VERSION 5.7 ;
BUSBITCHARS "[]" ;
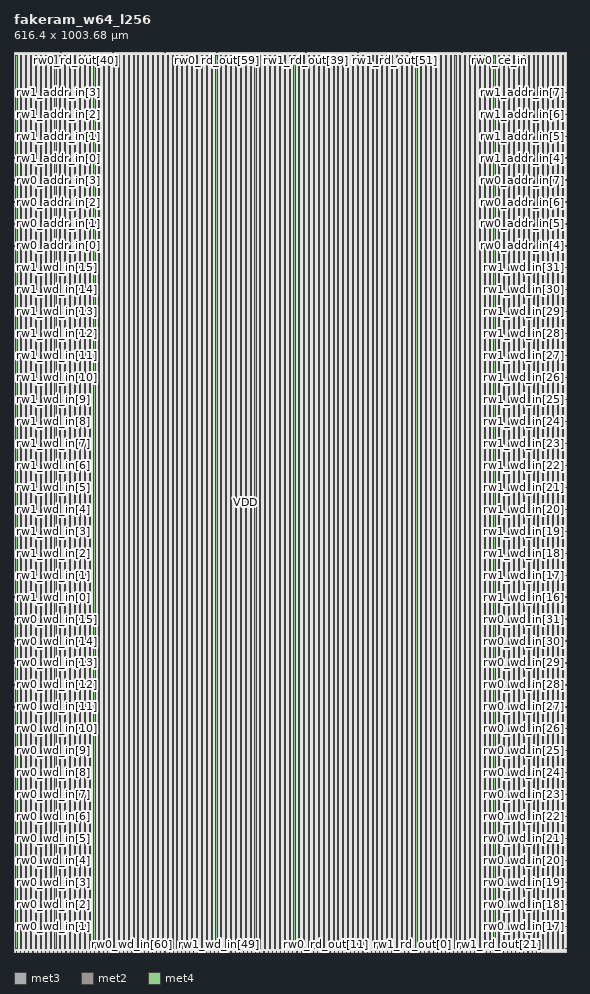
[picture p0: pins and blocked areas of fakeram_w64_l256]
MACRO fakeram_w64_l256
  FOREIGN fakeram_w64_l256 0 0 ;
  SYMMETRY X Y R90 ;
  SIZE 616.400 BY 1003.680 ;
  CLASS BLOCK ;
  PIN rw0_wd_in[0]
    DIRECTION INPUT ;
    USE SIGNAL ;
    SHAPE ABUTMENT ;
    PORT
      LAYER met3 ;
      RECT 0.000 3.930 0.900 4.230 ;
    END
  END rw0_wd_in[0]
  PIN rw0_wd_in[1]
    DIRECTION INPUT ;
    USE SIGNAL ;
    SHAPE ABUTMENT ;
    PORT
      LAYER met3 ;
      RECT 0.000 28.410 0.900 28.710 ;
    END
  END rw0_wd_in[1]
  PIN rw0_wd_in[2]
    DIRECTION INPUT ;
    USE SIGNAL ;
    SHAPE ABUTMENT ;
    PORT
      LAYER met3 ;
      RECT 0.000 52.890 0.900 53.190 ;
    END
  END rw0_wd_in[2]
  PIN rw0_wd_in[3]
    DIRECTION INPUT ;
    USE SIGNAL ;
    SHAPE ABUTMENT ;
    PORT
      LAYER met3 ;
      RECT 0.000 77.370 0.900 77.670 ;
    END
  END rw0_wd_in[3]
  PIN rw0_wd_in[4]
    DIRECTION INPUT ;
    USE SIGNAL ;
    SHAPE ABUTMENT ;
    PORT
      LAYER met3 ;
      RECT 0.000 101.850 0.900 102.150 ;
    END
  END rw0_wd_in[4]
  PIN rw0_wd_in[5]
    DIRECTION INPUT ;
    USE SIGNAL ;
    SHAPE ABUTMENT ;
    PORT
      LAYER met3 ;
      RECT 0.000 126.330 0.900 126.630 ;
    END
  END rw0_wd_in[5]
  PIN rw0_wd_in[6]
    DIRECTION INPUT ;
    USE SIGNAL ;
    SHAPE ABUTMENT ;
    PORT
      LAYER met3 ;
      RECT 0.000 150.810 0.900 151.110 ;
    END
  END rw0_wd_in[6]
  PIN rw0_wd_in[7]
    DIRECTION INPUT ;
    USE SIGNAL ;
    SHAPE ABUTMENT ;
    PORT
      LAYER met3 ;
      RECT 0.000 175.290 0.900 175.590 ;
    END
  END rw0_wd_in[7]
  PIN rw0_wd_in[8]
    DIRECTION INPUT ;
    USE SIGNAL ;
    SHAPE ABUTMENT ;
    PORT
      LAYER met3 ;
      RECT 0.000 199.770 0.900 200.070 ;
    END
  END rw0_wd_in[8]
  PIN rw0_wd_in[9]
    DIRECTION INPUT ;
    USE SIGNAL ;
    SHAPE ABUTMENT ;
    PORT
      LAYER met3 ;
      RECT 0.000 224.250 0.900 224.550 ;
    END
  END rw0_wd_in[9]
  PIN rw0_wd_in[10]
    DIRECTION INPUT ;
    USE SIGNAL ;
    SHAPE ABUTMENT ;
    PORT
      LAYER met3 ;
      RECT 0.000 248.730 0.900 249.030 ;
    END
  END rw0_wd_in[10]
  PIN rw0_wd_in[11]
    DIRECTION INPUT ;
    USE SIGNAL ;
    SHAPE ABUTMENT ;
    PORT
      LAYER met3 ;
      RECT 0.000 273.210 0.900 273.510 ;
    END
  END rw0_wd_in[11]
  PIN rw0_wd_in[12]
    DIRECTION INPUT ;
    USE SIGNAL ;
    SHAPE ABUTMENT ;
    PORT
      LAYER met3 ;
      RECT 0.000 297.690 0.900 297.990 ;
    END
  END rw0_wd_in[12]
  PIN rw0_wd_in[13]
    DIRECTION INPUT ;
    USE SIGNAL ;
    SHAPE ABUTMENT ;
    PORT
      LAYER met3 ;
      RECT 0.000 322.170 0.900 322.470 ;
    END
  END rw0_wd_in[13]
  PIN rw0_wd_in[14]
    DIRECTION INPUT ;
    USE SIGNAL ;
    SHAPE ABUTMENT ;
    PORT
      LAYER met3 ;
      RECT 0.000 346.650 0.900 346.950 ;
    END
  END rw0_wd_in[14]
  PIN rw0_wd_in[15]
    DIRECTION INPUT ;
    USE SIGNAL ;
    SHAPE ABUTMENT ;
    PORT
      LAYER met3 ;
      RECT 0.000 371.130 0.900 371.430 ;
    END
  END rw0_wd_in[15]
  PIN rw0_wd_in[16]
    DIRECTION INPUT ;
    USE SIGNAL ;
    SHAPE ABUTMENT ;
    PORT
      LAYER met3 ;
      RECT 615.500 3.930 616.400 4.230 ;
    END
  END rw0_wd_in[16]
  PIN rw0_wd_in[17]
    DIRECTION INPUT ;
    USE SIGNAL ;
    SHAPE ABUTMENT ;
    PORT
      LAYER met3 ;
      RECT 615.500 28.410 616.400 28.710 ;
    END
  END rw0_wd_in[17]
  PIN rw0_wd_in[18]
    DIRECTION INPUT ;
    USE SIGNAL ;
    SHAPE ABUTMENT ;
    PORT
      LAYER met3 ;
      RECT 615.500 52.890 616.400 53.190 ;
    END
  END rw0_wd_in[18]
  PIN rw0_wd_in[19]
    DIRECTION INPUT ;
    USE SIGNAL ;
    SHAPE ABUTMENT ;
    PORT
      LAYER met3 ;
      RECT 615.500 77.370 616.400 77.670 ;
    END
  END rw0_wd_in[19]
  PIN rw0_wd_in[20]
    DIRECTION INPUT ;
    USE SIGNAL ;
    SHAPE ABUTMENT ;
    PORT
      LAYER met3 ;
      RECT 615.500 101.850 616.400 102.150 ;
    END
  END rw0_wd_in[20]
  PIN rw0_wd_in[21]
    DIRECTION INPUT ;
    USE SIGNAL ;
    SHAPE ABUTMENT ;
    PORT
      LAYER met3 ;
      RECT 615.500 126.330 616.400 126.630 ;
    END
  END rw0_wd_in[21]
  PIN rw0_wd_in[22]
    DIRECTION INPUT ;
    USE SIGNAL ;
    SHAPE ABUTMENT ;
    PORT
      LAYER met3 ;
      RECT 615.500 150.810 616.400 151.110 ;
    END
  END rw0_wd_in[22]
  PIN rw0_wd_in[23]
    DIRECTION INPUT ;
    USE SIGNAL ;
    SHAPE ABUTMENT ;
    PORT
      LAYER met3 ;
      RECT 615.500 175.290 616.400 175.590 ;
    END
  END rw0_wd_in[23]
  PIN rw0_wd_in[24]
    DIRECTION INPUT ;
    USE SIGNAL ;
    SHAPE ABUTMENT ;
    PORT
      LAYER met3 ;
      RECT 615.500 199.770 616.400 200.070 ;
    END
  END rw0_wd_in[24]
  PIN rw0_wd_in[25]
    DIRECTION INPUT ;
    USE SIGNAL ;
    SHAPE ABUTMENT ;
    PORT
      LAYER met3 ;
      RECT 615.500 224.250 616.400 224.550 ;
    END
  END rw0_wd_in[25]
  PIN rw0_wd_in[26]
    DIRECTION INPUT ;
    USE SIGNAL ;
    SHAPE ABUTMENT ;
    PORT
      LAYER met3 ;
      RECT 615.500 248.730 616.400 249.030 ;
    END
  END rw0_wd_in[26]
  PIN rw0_wd_in[27]
    DIRECTION INPUT ;
    USE SIGNAL ;
    SHAPE ABUTMENT ;
    PORT
      LAYER met3 ;
      RECT 615.500 273.210 616.400 273.510 ;
    END
  END rw0_wd_in[27]
  PIN rw0_wd_in[28]
    DIRECTION INPUT ;
    USE SIGNAL ;
    SHAPE ABUTMENT ;
    PORT
      LAYER met3 ;
      RECT 615.500 297.690 616.400 297.990 ;
    END
  END rw0_wd_in[28]
  PIN rw0_wd_in[29]
    DIRECTION INPUT ;
    USE SIGNAL ;
    SHAPE ABUTMENT ;
    PORT
      LAYER met3 ;
      RECT 615.500 322.170 616.400 322.470 ;
    END
  END rw0_wd_in[29]
  PIN rw0_wd_in[30]
    DIRECTION INPUT ;
    USE SIGNAL ;
    SHAPE ABUTMENT ;
    PORT
      LAYER met3 ;
      RECT 615.500 346.650 616.400 346.950 ;
    END
  END rw0_wd_in[30]
  PIN rw0_wd_in[31]
    DIRECTION INPUT ;
    USE SIGNAL ;
    SHAPE ABUTMENT ;
    PORT
      LAYER met3 ;
      RECT 615.500 371.130 616.400 371.430 ;
    END
  END rw0_wd_in[31]
  PIN rw0_wd_in[32]
    DIRECTION INPUT ;
    USE SIGNAL ;
    SHAPE ABUTMENT ;
    PORT
      LAYER met2 ;
      RECT 2.690 0.000 2.830 0.420 ;
    END
  END rw0_wd_in[32]
  PIN rw0_wd_in[33]
    DIRECTION INPUT ;
    USE SIGNAL ;
    SHAPE ABUTMENT ;
    PORT
      LAYER met2 ;
      RECT 7.290 0.000 7.430 0.420 ;
    END
  END rw0_wd_in[33]
  PIN rw0_wd_in[34]
    DIRECTION INPUT ;
    USE SIGNAL ;
    SHAPE ABUTMENT ;
    PORT
      LAYER met2 ;
      RECT 11.890 0.000 12.030 0.420 ;
    END
  END rw0_wd_in[34]
  PIN rw0_wd_in[35]
    DIRECTION INPUT ;
    USE SIGNAL ;
    SHAPE ABUTMENT ;
    PORT
      LAYER met2 ;
      RECT 16.490 0.000 16.630 0.420 ;
    END
  END rw0_wd_in[35]
  PIN rw0_wd_in[36]
    DIRECTION INPUT ;
    USE SIGNAL ;
    SHAPE ABUTMENT ;
    PORT
      LAYER met2 ;
      RECT 21.090 0.000 21.230 0.420 ;
    END
  END rw0_wd_in[36]
  PIN rw0_wd_in[37]
    DIRECTION INPUT ;
    USE SIGNAL ;
    SHAPE ABUTMENT ;
    PORT
      LAYER met2 ;
      RECT 25.690 0.000 25.830 0.420 ;
    END
  END rw0_wd_in[37]
  PIN rw0_wd_in[38]
    DIRECTION INPUT ;
    USE SIGNAL ;
    SHAPE ABUTMENT ;
    PORT
      LAYER met2 ;
      RECT 30.290 0.000 30.430 0.420 ;
    END
  END rw0_wd_in[38]
  PIN rw0_wd_in[39]
    DIRECTION INPUT ;
    USE SIGNAL ;
    SHAPE ABUTMENT ;
    PORT
      LAYER met2 ;
      RECT 34.890 0.000 35.030 0.420 ;
    END
  END rw0_wd_in[39]
  PIN rw0_wd_in[40]
    DIRECTION INPUT ;
    USE SIGNAL ;
    SHAPE ABUTMENT ;
    PORT
      LAYER met2 ;
      RECT 39.490 0.000 39.630 0.420 ;
    END
  END rw0_wd_in[40]
  PIN rw0_wd_in[41]
    DIRECTION INPUT ;
    USE SIGNAL ;
    SHAPE ABUTMENT ;
    PORT
      LAYER met2 ;
      RECT 44.090 0.000 44.230 0.420 ;
    END
  END rw0_wd_in[41]
  PIN rw0_wd_in[42]
    DIRECTION INPUT ;
    USE SIGNAL ;
    SHAPE ABUTMENT ;
    PORT
      LAYER met2 ;
      RECT 48.690 0.000 48.830 0.420 ;
    END
  END rw0_wd_in[42]
  PIN rw0_wd_in[43]
    DIRECTION INPUT ;
    USE SIGNAL ;
    SHAPE ABUTMENT ;
    PORT
      LAYER met2 ;
      RECT 53.290 0.000 53.430 0.420 ;
    END
  END rw0_wd_in[43]
  PIN rw0_wd_in[44]
    DIRECTION INPUT ;
    USE SIGNAL ;
    SHAPE ABUTMENT ;
    PORT
      LAYER met2 ;
      RECT 57.890 0.000 58.030 0.420 ;
    END
  END rw0_wd_in[44]
  PIN rw0_wd_in[45]
    DIRECTION INPUT ;
    USE SIGNAL ;
    SHAPE ABUTMENT ;
    PORT
      LAYER met2 ;
      RECT 62.490 0.000 62.630 0.420 ;
    END
  END rw0_wd_in[45]
  PIN rw0_wd_in[46]
    DIRECTION INPUT ;
    USE SIGNAL ;
    SHAPE ABUTMENT ;
    PORT
      LAYER met2 ;
      RECT 67.090 0.000 67.230 0.420 ;
    END
  END rw0_wd_in[46]
  PIN rw0_wd_in[47]
    DIRECTION INPUT ;
    USE SIGNAL ;
    SHAPE ABUTMENT ;
    PORT
      LAYER met2 ;
      RECT 71.690 0.000 71.830 0.420 ;
    END
  END rw0_wd_in[47]
  PIN rw0_wd_in[48]
    DIRECTION INPUT ;
    USE SIGNAL ;
    SHAPE ABUTMENT ;
    PORT
      LAYER met2 ;
      RECT 76.290 0.000 76.430 0.420 ;
    END
  END rw0_wd_in[48]
  PIN rw0_wd_in[49]
    DIRECTION INPUT ;
    USE SIGNAL ;
    SHAPE ABUTMENT ;
    PORT
      LAYER met2 ;
      RECT 80.890 0.000 81.030 0.420 ;
    END
  END rw0_wd_in[49]
  PIN rw0_wd_in[50]
    DIRECTION INPUT ;
    USE SIGNAL ;
    SHAPE ABUTMENT ;
    PORT
      LAYER met2 ;
      RECT 85.490 0.000 85.630 0.420 ;
    END
  END rw0_wd_in[50]
  PIN rw0_wd_in[51]
    DIRECTION INPUT ;
    USE SIGNAL ;
    SHAPE ABUTMENT ;
    PORT
      LAYER met2 ;
      RECT 90.090 0.000 90.230 0.420 ;
    END
  END rw0_wd_in[51]
  PIN rw0_wd_in[52]
    DIRECTION INPUT ;
    USE SIGNAL ;
    SHAPE ABUTMENT ;
    PORT
      LAYER met2 ;
      RECT 94.690 0.000 94.830 0.420 ;
    END
  END rw0_wd_in[52]
  PIN rw0_wd_in[53]
    DIRECTION INPUT ;
    USE SIGNAL ;
    SHAPE ABUTMENT ;
    PORT
      LAYER met2 ;
      RECT 99.290 0.000 99.430 0.420 ;
    END
  END rw0_wd_in[53]
  PIN rw0_wd_in[54]
    DIRECTION INPUT ;
    USE SIGNAL ;
    SHAPE ABUTMENT ;
    PORT
      LAYER met2 ;
      RECT 103.890 0.000 104.030 0.420 ;
    END
  END rw0_wd_in[54]
  PIN rw0_wd_in[55]
    DIRECTION INPUT ;
    USE SIGNAL ;
    SHAPE ABUTMENT ;
    PORT
      LAYER met2 ;
      RECT 108.490 0.000 108.630 0.420 ;
    END
  END rw0_wd_in[55]
  PIN rw0_wd_in[56]
    DIRECTION INPUT ;
    USE SIGNAL ;
    SHAPE ABUTMENT ;
    PORT
      LAYER met2 ;
      RECT 113.090 0.000 113.230 0.420 ;
    END
  END rw0_wd_in[56]
  PIN rw0_wd_in[57]
    DIRECTION INPUT ;
    USE SIGNAL ;
    SHAPE ABUTMENT ;
    PORT
      LAYER met2 ;
      RECT 117.690 0.000 117.830 0.420 ;
    END
  END rw0_wd_in[57]
  PIN rw0_wd_in[58]
    DIRECTION INPUT ;
    USE SIGNAL ;
    SHAPE ABUTMENT ;
    PORT
      LAYER met2 ;
      RECT 122.290 0.000 122.430 0.420 ;
    END
  END rw0_wd_in[58]
  PIN rw0_wd_in[59]
    DIRECTION INPUT ;
    USE SIGNAL ;
    SHAPE ABUTMENT ;
    PORT
      LAYER met2 ;
      RECT 126.890 0.000 127.030 0.420 ;
    END
  END rw0_wd_in[59]
  PIN rw0_wd_in[60]
    DIRECTION INPUT ;
    USE SIGNAL ;
    SHAPE ABUTMENT ;
    PORT
      LAYER met2 ;
      RECT 131.490 0.000 131.630 0.420 ;
    END
  END rw0_wd_in[60]
  PIN rw0_wd_in[61]
    DIRECTION INPUT ;
    USE SIGNAL ;
    SHAPE ABUTMENT ;
    PORT
      LAYER met2 ;
      RECT 136.090 0.000 136.230 0.420 ;
    END
  END rw0_wd_in[61]
  PIN rw0_wd_in[62]
    DIRECTION INPUT ;
    USE SIGNAL ;
    SHAPE ABUTMENT ;
    PORT
      LAYER met2 ;
      RECT 140.690 0.000 140.830 0.420 ;
    END
  END rw0_wd_in[62]
  PIN rw0_wd_in[63]
    DIRECTION INPUT ;
    USE SIGNAL ;
    SHAPE ABUTMENT ;
    PORT
      LAYER met2 ;
      RECT 145.290 0.000 145.430 0.420 ;
    END
  END rw0_wd_in[63]
  PIN rw1_wd_in[0]
    DIRECTION INPUT ;
    USE SIGNAL ;
    SHAPE ABUTMENT ;
    PORT
      LAYER met3 ;
      RECT 0.000 395.610 0.900 395.910 ;
    END
  END rw1_wd_in[0]
  PIN rw1_wd_in[1]
    DIRECTION INPUT ;
    USE SIGNAL ;
    SHAPE ABUTMENT ;
    PORT
      LAYER met3 ;
      RECT 0.000 420.090 0.900 420.390 ;
    END
  END rw1_wd_in[1]
  PIN rw1_wd_in[2]
    DIRECTION INPUT ;
    USE SIGNAL ;
    SHAPE ABUTMENT ;
    PORT
      LAYER met3 ;
      RECT 0.000 444.570 0.900 444.870 ;
    END
  END rw1_wd_in[2]
  PIN rw1_wd_in[3]
    DIRECTION INPUT ;
    USE SIGNAL ;
    SHAPE ABUTMENT ;
    PORT
      LAYER met3 ;
      RECT 0.000 469.050 0.900 469.350 ;
    END
  END rw1_wd_in[3]
  PIN rw1_wd_in[4]
    DIRECTION INPUT ;
    USE SIGNAL ;
    SHAPE ABUTMENT ;
    PORT
      LAYER met3 ;
      RECT 0.000 493.530 0.900 493.830 ;
    END
  END rw1_wd_in[4]
  PIN rw1_wd_in[5]
    DIRECTION INPUT ;
    USE SIGNAL ;
    SHAPE ABUTMENT ;
    PORT
      LAYER met3 ;
      RECT 0.000 518.010 0.900 518.310 ;
    END
  END rw1_wd_in[5]
  PIN rw1_wd_in[6]
    DIRECTION INPUT ;
    USE SIGNAL ;
    SHAPE ABUTMENT ;
    PORT
      LAYER met3 ;
      RECT 0.000 542.490 0.900 542.790 ;
    END
  END rw1_wd_in[6]
  PIN rw1_wd_in[7]
    DIRECTION INPUT ;
    USE SIGNAL ;
    SHAPE ABUTMENT ;
    PORT
      LAYER met3 ;
      RECT 0.000 566.970 0.900 567.270 ;
    END
  END rw1_wd_in[7]
  PIN rw1_wd_in[8]
    DIRECTION INPUT ;
    USE SIGNAL ;
    SHAPE ABUTMENT ;
    PORT
      LAYER met3 ;
      RECT 0.000 591.450 0.900 591.750 ;
    END
  END rw1_wd_in[8]
  PIN rw1_wd_in[9]
    DIRECTION INPUT ;
    USE SIGNAL ;
    SHAPE ABUTMENT ;
    PORT
      LAYER met3 ;
      RECT 0.000 615.930 0.900 616.230 ;
    END
  END rw1_wd_in[9]
  PIN rw1_wd_in[10]
    DIRECTION INPUT ;
    USE SIGNAL ;
    SHAPE ABUTMENT ;
    PORT
      LAYER met3 ;
      RECT 0.000 640.410 0.900 640.710 ;
    END
  END rw1_wd_in[10]
  PIN rw1_wd_in[11]
    DIRECTION INPUT ;
    USE SIGNAL ;
    SHAPE ABUTMENT ;
    PORT
      LAYER met3 ;
      RECT 0.000 664.890 0.900 665.190 ;
    END
  END rw1_wd_in[11]
  PIN rw1_wd_in[12]
    DIRECTION INPUT ;
    USE SIGNAL ;
    SHAPE ABUTMENT ;
    PORT
      LAYER met3 ;
      RECT 0.000 689.370 0.900 689.670 ;
    END
  END rw1_wd_in[12]
  PIN rw1_wd_in[13]
    DIRECTION INPUT ;
    USE SIGNAL ;
    SHAPE ABUTMENT ;
    PORT
      LAYER met3 ;
      RECT 0.000 713.850 0.900 714.150 ;
    END
  END rw1_wd_in[13]
  PIN rw1_wd_in[14]
    DIRECTION INPUT ;
    USE SIGNAL ;
    SHAPE ABUTMENT ;
    PORT
      LAYER met3 ;
      RECT 0.000 738.330 0.900 738.630 ;
    END
  END rw1_wd_in[14]
  PIN rw1_wd_in[15]
    DIRECTION INPUT ;
    USE SIGNAL ;
    SHAPE ABUTMENT ;
    PORT
      LAYER met3 ;
      RECT 0.000 762.810 0.900 763.110 ;
    END
  END rw1_wd_in[15]
  PIN rw1_wd_in[16]
    DIRECTION INPUT ;
    USE SIGNAL ;
    SHAPE ABUTMENT ;
    PORT
      LAYER met3 ;
      RECT 615.500 395.610 616.400 395.910 ;
    END
  END rw1_wd_in[16]
  PIN rw1_wd_in[17]
    DIRECTION INPUT ;
    USE SIGNAL ;
    SHAPE ABUTMENT ;
    PORT
      LAYER met3 ;
      RECT 615.500 420.090 616.400 420.390 ;
    END
  END rw1_wd_in[17]
  PIN rw1_wd_in[18]
    DIRECTION INPUT ;
    USE SIGNAL ;
    SHAPE ABUTMENT ;
    PORT
      LAYER met3 ;
      RECT 615.500 444.570 616.400 444.870 ;
    END
  END rw1_wd_in[18]
  PIN rw1_wd_in[19]
    DIRECTION INPUT ;
    USE SIGNAL ;
    SHAPE ABUTMENT ;
    PORT
      LAYER met3 ;
      RECT 615.500 469.050 616.400 469.350 ;
    END
  END rw1_wd_in[19]
  PIN rw1_wd_in[20]
    DIRECTION INPUT ;
    USE SIGNAL ;
    SHAPE ABUTMENT ;
    PORT
      LAYER met3 ;
      RECT 615.500 493.530 616.400 493.830 ;
    END
  END rw1_wd_in[20]
  PIN rw1_wd_in[21]
    DIRECTION INPUT ;
    USE SIGNAL ;
    SHAPE ABUTMENT ;
    PORT
      LAYER met3 ;
      RECT 615.500 518.010 616.400 518.310 ;
    END
  END rw1_wd_in[21]
  PIN rw1_wd_in[22]
    DIRECTION INPUT ;
    USE SIGNAL ;
    SHAPE ABUTMENT ;
    PORT
      LAYER met3 ;
      RECT 615.500 542.490 616.400 542.790 ;
    END
  END rw1_wd_in[22]
  PIN rw1_wd_in[23]
    DIRECTION INPUT ;
    USE SIGNAL ;
    SHAPE ABUTMENT ;
    PORT
      LAYER met3 ;
      RECT 615.500 566.970 616.400 567.270 ;
    END
  END rw1_wd_in[23]
  PIN rw1_wd_in[24]
    DIRECTION INPUT ;
    USE SIGNAL ;
    SHAPE ABUTMENT ;
    PORT
      LAYER met3 ;
      RECT 615.500 591.450 616.400 591.750 ;
    END
  END rw1_wd_in[24]
  PIN rw1_wd_in[25]
    DIRECTION INPUT ;
    USE SIGNAL ;
    SHAPE ABUTMENT ;
    PORT
      LAYER met3 ;
      RECT 615.500 615.930 616.400 616.230 ;
    END
  END rw1_wd_in[25]
  PIN rw1_wd_in[26]
    DIRECTION INPUT ;
    USE SIGNAL ;
    SHAPE ABUTMENT ;
    PORT
      LAYER met3 ;
      RECT 615.500 640.410 616.400 640.710 ;
    END
  END rw1_wd_in[26]
  PIN rw1_wd_in[27]
    DIRECTION INPUT ;
    USE SIGNAL ;
    SHAPE ABUTMENT ;
    PORT
      LAYER met3 ;
      RECT 615.500 664.890 616.400 665.190 ;
    END
  END rw1_wd_in[27]
  PIN rw1_wd_in[28]
    DIRECTION INPUT ;
    USE SIGNAL ;
    SHAPE ABUTMENT ;
    PORT
      LAYER met3 ;
      RECT 615.500 689.370 616.400 689.670 ;
    END
  END rw1_wd_in[28]
  PIN rw1_wd_in[29]
    DIRECTION INPUT ;
    USE SIGNAL ;
    SHAPE ABUTMENT ;
    PORT
      LAYER met3 ;
      RECT 615.500 713.850 616.400 714.150 ;
    END
  END rw1_wd_in[29]
  PIN rw1_wd_in[30]
    DIRECTION INPUT ;
    USE SIGNAL ;
    SHAPE ABUTMENT ;
    PORT
      LAYER met3 ;
      RECT 615.500 738.330 616.400 738.630 ;
    END
  END rw1_wd_in[30]
  PIN rw1_wd_in[31]
    DIRECTION INPUT ;
    USE SIGNAL ;
    SHAPE ABUTMENT ;
    PORT
      LAYER met3 ;
      RECT 615.500 762.810 616.400 763.110 ;
    END
  END rw1_wd_in[31]
  PIN rw1_wd_in[32]
    DIRECTION INPUT ;
    USE SIGNAL ;
    SHAPE ABUTMENT ;
    PORT
      LAYER met2 ;
      RECT 149.890 0.000 150.030 0.420 ;
    END
  END rw1_wd_in[32]
  PIN rw1_wd_in[33]
    DIRECTION INPUT ;
    USE SIGNAL ;
    SHAPE ABUTMENT ;
    PORT
      LAYER met2 ;
      RECT 154.490 0.000 154.630 0.420 ;
    END
  END rw1_wd_in[33]
  PIN rw1_wd_in[34]
    DIRECTION INPUT ;
    USE SIGNAL ;
    SHAPE ABUTMENT ;
    PORT
      LAYER met2 ;
      RECT 159.090 0.000 159.230 0.420 ;
    END
  END rw1_wd_in[34]
  PIN rw1_wd_in[35]
    DIRECTION INPUT ;
    USE SIGNAL ;
    SHAPE ABUTMENT ;
    PORT
      LAYER met2 ;
      RECT 163.690 0.000 163.830 0.420 ;
    END
  END rw1_wd_in[35]
  PIN rw1_wd_in[36]
    DIRECTION INPUT ;
    USE SIGNAL ;
    SHAPE ABUTMENT ;
    PORT
      LAYER met2 ;
      RECT 168.290 0.000 168.430 0.420 ;
    END
  END rw1_wd_in[36]
  PIN rw1_wd_in[37]
    DIRECTION INPUT ;
    USE SIGNAL ;
    SHAPE ABUTMENT ;
    PORT
      LAYER met2 ;
      RECT 172.890 0.000 173.030 0.420 ;
    END
  END rw1_wd_in[37]
  PIN rw1_wd_in[38]
    DIRECTION INPUT ;
    USE SIGNAL ;
    SHAPE ABUTMENT ;
    PORT
      LAYER met2 ;
      RECT 177.490 0.000 177.630 0.420 ;
    END
  END rw1_wd_in[38]
  PIN rw1_wd_in[39]
    DIRECTION INPUT ;
    USE SIGNAL ;
    SHAPE ABUTMENT ;
    PORT
      LAYER met2 ;
      RECT 182.090 0.000 182.230 0.420 ;
    END
  END rw1_wd_in[39]
  PIN rw1_wd_in[40]
    DIRECTION INPUT ;
    USE SIGNAL ;
    SHAPE ABUTMENT ;
    PORT
      LAYER met2 ;
      RECT 186.690 0.000 186.830 0.420 ;
    END
  END rw1_wd_in[40]
  PIN rw1_wd_in[41]
    DIRECTION INPUT ;
    USE SIGNAL ;
    SHAPE ABUTMENT ;
    PORT
      LAYER met2 ;
      RECT 191.290 0.000 191.430 0.420 ;
    END
  END rw1_wd_in[41]
  PIN rw1_wd_in[42]
    DIRECTION INPUT ;
    USE SIGNAL ;
    SHAPE ABUTMENT ;
    PORT
      LAYER met2 ;
      RECT 195.890 0.000 196.030 0.420 ;
    END
  END rw1_wd_in[42]
  PIN rw1_wd_in[43]
    DIRECTION INPUT ;
    USE SIGNAL ;
    SHAPE ABUTMENT ;
    PORT
      LAYER met2 ;
      RECT 200.490 0.000 200.630 0.420 ;
    END
  END rw1_wd_in[43]
  PIN rw1_wd_in[44]
    DIRECTION INPUT ;
    USE SIGNAL ;
    SHAPE ABUTMENT ;
    PORT
      LAYER met2 ;
      RECT 205.090 0.000 205.230 0.420 ;
    END
  END rw1_wd_in[44]
  PIN rw1_wd_in[45]
    DIRECTION INPUT ;
    USE SIGNAL ;
    SHAPE ABUTMENT ;
    PORT
      LAYER met2 ;
      RECT 209.690 0.000 209.830 0.420 ;
    END
  END rw1_wd_in[45]
  PIN rw1_wd_in[46]
    DIRECTION INPUT ;
    USE SIGNAL ;
    SHAPE ABUTMENT ;
    PORT
      LAYER met2 ;
      RECT 214.290 0.000 214.430 0.420 ;
    END
  END rw1_wd_in[46]
  PIN rw1_wd_in[47]
    DIRECTION INPUT ;
    USE SIGNAL ;
    SHAPE ABUTMENT ;
    PORT
      LAYER met2 ;
      RECT 218.890 0.000 219.030 0.420 ;
    END
  END rw1_wd_in[47]
  PIN rw1_wd_in[48]
    DIRECTION INPUT ;
    USE SIGNAL ;
    SHAPE ABUTMENT ;
    PORT
      LAYER met2 ;
      RECT 223.490 0.000 223.630 0.420 ;
    END
  END rw1_wd_in[48]
  PIN rw1_wd_in[49]
    DIRECTION INPUT ;
    USE SIGNAL ;
    SHAPE ABUTMENT ;
    PORT
      LAYER met2 ;
      RECT 228.090 0.000 228.230 0.420 ;
    END
  END rw1_wd_in[49]
  PIN rw1_wd_in[50]
    DIRECTION INPUT ;
    USE SIGNAL ;
    SHAPE ABUTMENT ;
    PORT
      LAYER met2 ;
      RECT 232.690 0.000 232.830 0.420 ;
    END
  END rw1_wd_in[50]
  PIN rw1_wd_in[51]
    DIRECTION INPUT ;
    USE SIGNAL ;
    SHAPE ABUTMENT ;
    PORT
      LAYER met2 ;
      RECT 237.290 0.000 237.430 0.420 ;
    END
  END rw1_wd_in[51]
  PIN rw1_wd_in[52]
    DIRECTION INPUT ;
    USE SIGNAL ;
    SHAPE ABUTMENT ;
    PORT
      LAYER met2 ;
      RECT 241.890 0.000 242.030 0.420 ;
    END
  END rw1_wd_in[52]
  PIN rw1_wd_in[53]
    DIRECTION INPUT ;
    USE SIGNAL ;
    SHAPE ABUTMENT ;
    PORT
      LAYER met2 ;
      RECT 246.490 0.000 246.630 0.420 ;
    END
  END rw1_wd_in[53]
  PIN rw1_wd_in[54]
    DIRECTION INPUT ;
    USE SIGNAL ;
    SHAPE ABUTMENT ;
    PORT
      LAYER met2 ;
      RECT 251.090 0.000 251.230 0.420 ;
    END
  END rw1_wd_in[54]
  PIN rw1_wd_in[55]
    DIRECTION INPUT ;
    USE SIGNAL ;
    SHAPE ABUTMENT ;
    PORT
      LAYER met2 ;
      RECT 255.690 0.000 255.830 0.420 ;
    END
  END rw1_wd_in[55]
  PIN rw1_wd_in[56]
    DIRECTION INPUT ;
    USE SIGNAL ;
    SHAPE ABUTMENT ;
    PORT
      LAYER met2 ;
      RECT 260.290 0.000 260.430 0.420 ;
    END
  END rw1_wd_in[56]
  PIN rw1_wd_in[57]
    DIRECTION INPUT ;
    USE SIGNAL ;
    SHAPE ABUTMENT ;
    PORT
      LAYER met2 ;
      RECT 264.890 0.000 265.030 0.420 ;
    END
  END rw1_wd_in[57]
  PIN rw1_wd_in[58]
    DIRECTION INPUT ;
    USE SIGNAL ;
    SHAPE ABUTMENT ;
    PORT
      LAYER met2 ;
      RECT 269.490 0.000 269.630 0.420 ;
    END
  END rw1_wd_in[58]
  PIN rw1_wd_in[59]
    DIRECTION INPUT ;
    USE SIGNAL ;
    SHAPE ABUTMENT ;
    PORT
      LAYER met2 ;
      RECT 274.090 0.000 274.230 0.420 ;
    END
  END rw1_wd_in[59]
  PIN rw1_wd_in[60]
    DIRECTION INPUT ;
    USE SIGNAL ;
    SHAPE ABUTMENT ;
    PORT
      LAYER met2 ;
      RECT 278.690 0.000 278.830 0.420 ;
    END
  END rw1_wd_in[60]
  PIN rw1_wd_in[61]
    DIRECTION INPUT ;
    USE SIGNAL ;
    SHAPE ABUTMENT ;
    PORT
      LAYER met2 ;
      RECT 283.290 0.000 283.430 0.420 ;
    END
  END rw1_wd_in[61]
  PIN rw1_wd_in[62]
    DIRECTION INPUT ;
    USE SIGNAL ;
    SHAPE ABUTMENT ;
    PORT
      LAYER met2 ;
      RECT 287.890 0.000 288.030 0.420 ;
    END
  END rw1_wd_in[62]
  PIN rw1_wd_in[63]
    DIRECTION INPUT ;
    USE SIGNAL ;
    SHAPE ABUTMENT ;
    PORT
      LAYER met2 ;
      RECT 292.490 0.000 292.630 0.420 ;
    END
  END rw1_wd_in[63]
  PIN rw0_rd_out[0]
    DIRECTION OUTPUT ;
    USE SIGNAL ;
    SHAPE ABUTMENT ;
    PORT
      LAYER met2 ;
      RECT 297.090 0.000 297.230 0.420 ;
    END
  END rw0_rd_out[0]
  PIN rw0_rd_out[1]
    DIRECTION OUTPUT ;
    USE SIGNAL ;
    SHAPE ABUTMENT ;
    PORT
      LAYER met2 ;
      RECT 301.690 0.000 301.830 0.420 ;
    END
  END rw0_rd_out[1]
  PIN rw0_rd_out[2]
    DIRECTION OUTPUT ;
    USE SIGNAL ;
    SHAPE ABUTMENT ;
    PORT
      LAYER met2 ;
      RECT 306.290 0.000 306.430 0.420 ;
    END
  END rw0_rd_out[2]
  PIN rw0_rd_out[3]
    DIRECTION OUTPUT ;
    USE SIGNAL ;
    SHAPE ABUTMENT ;
    PORT
      LAYER met2 ;
      RECT 310.890 0.000 311.030 0.420 ;
    END
  END rw0_rd_out[3]
  PIN rw0_rd_out[4]
    DIRECTION OUTPUT ;
    USE SIGNAL ;
    SHAPE ABUTMENT ;
    PORT
      LAYER met2 ;
      RECT 315.490 0.000 315.630 0.420 ;
    END
  END rw0_rd_out[4]
  PIN rw0_rd_out[5]
    DIRECTION OUTPUT ;
    USE SIGNAL ;
    SHAPE ABUTMENT ;
    PORT
      LAYER met2 ;
      RECT 320.090 0.000 320.230 0.420 ;
    END
  END rw0_rd_out[5]
  PIN rw0_rd_out[6]
    DIRECTION OUTPUT ;
    USE SIGNAL ;
    SHAPE ABUTMENT ;
    PORT
      LAYER met2 ;
      RECT 324.690 0.000 324.830 0.420 ;
    END
  END rw0_rd_out[6]
  PIN rw0_rd_out[7]
    DIRECTION OUTPUT ;
    USE SIGNAL ;
    SHAPE ABUTMENT ;
    PORT
      LAYER met2 ;
      RECT 329.290 0.000 329.430 0.420 ;
    END
  END rw0_rd_out[7]
  PIN rw0_rd_out[8]
    DIRECTION OUTPUT ;
    USE SIGNAL ;
    SHAPE ABUTMENT ;
    PORT
      LAYER met2 ;
      RECT 333.890 0.000 334.030 0.420 ;
    END
  END rw0_rd_out[8]
  PIN rw0_rd_out[9]
    DIRECTION OUTPUT ;
    USE SIGNAL ;
    SHAPE ABUTMENT ;
    PORT
      LAYER met2 ;
      RECT 338.490 0.000 338.630 0.420 ;
    END
  END rw0_rd_out[9]
  PIN rw0_rd_out[10]
    DIRECTION OUTPUT ;
    USE SIGNAL ;
    SHAPE ABUTMENT ;
    PORT
      LAYER met2 ;
      RECT 343.090 0.000 343.230 0.420 ;
    END
  END rw0_rd_out[10]
  PIN rw0_rd_out[11]
    DIRECTION OUTPUT ;
    USE SIGNAL ;
    SHAPE ABUTMENT ;
    PORT
      LAYER met2 ;
      RECT 347.690 0.000 347.830 0.420 ;
    END
  END rw0_rd_out[11]
  PIN rw0_rd_out[12]
    DIRECTION OUTPUT ;
    USE SIGNAL ;
    SHAPE ABUTMENT ;
    PORT
      LAYER met2 ;
      RECT 352.290 0.000 352.430 0.420 ;
    END
  END rw0_rd_out[12]
  PIN rw0_rd_out[13]
    DIRECTION OUTPUT ;
    USE SIGNAL ;
    SHAPE ABUTMENT ;
    PORT
      LAYER met2 ;
      RECT 356.890 0.000 357.030 0.420 ;
    END
  END rw0_rd_out[13]
  PIN rw0_rd_out[14]
    DIRECTION OUTPUT ;
    USE SIGNAL ;
    SHAPE ABUTMENT ;
    PORT
      LAYER met2 ;
      RECT 361.490 0.000 361.630 0.420 ;
    END
  END rw0_rd_out[14]
  PIN rw0_rd_out[15]
    DIRECTION OUTPUT ;
    USE SIGNAL ;
    SHAPE ABUTMENT ;
    PORT
      LAYER met2 ;
      RECT 366.090 0.000 366.230 0.420 ;
    END
  END rw0_rd_out[15]
  PIN rw0_rd_out[16]
    DIRECTION OUTPUT ;
    USE SIGNAL ;
    SHAPE ABUTMENT ;
    PORT
      LAYER met2 ;
      RECT 370.690 0.000 370.830 0.420 ;
    END
  END rw0_rd_out[16]
  PIN rw0_rd_out[17]
    DIRECTION OUTPUT ;
    USE SIGNAL ;
    SHAPE ABUTMENT ;
    PORT
      LAYER met2 ;
      RECT 375.290 0.000 375.430 0.420 ;
    END
  END rw0_rd_out[17]
  PIN rw0_rd_out[18]
    DIRECTION OUTPUT ;
    USE SIGNAL ;
    SHAPE ABUTMENT ;
    PORT
      LAYER met2 ;
      RECT 379.890 0.000 380.030 0.420 ;
    END
  END rw0_rd_out[18]
  PIN rw0_rd_out[19]
    DIRECTION OUTPUT ;
    USE SIGNAL ;
    SHAPE ABUTMENT ;
    PORT
      LAYER met2 ;
      RECT 384.490 0.000 384.630 0.420 ;
    END
  END rw0_rd_out[19]
  PIN rw0_rd_out[20]
    DIRECTION OUTPUT ;
    USE SIGNAL ;
    SHAPE ABUTMENT ;
    PORT
      LAYER met2 ;
      RECT 389.090 0.000 389.230 0.420 ;
    END
  END rw0_rd_out[20]
  PIN rw0_rd_out[21]
    DIRECTION OUTPUT ;
    USE SIGNAL ;
    SHAPE ABUTMENT ;
    PORT
      LAYER met2 ;
      RECT 393.690 0.000 393.830 0.420 ;
    END
  END rw0_rd_out[21]
  PIN rw0_rd_out[22]
    DIRECTION OUTPUT ;
    USE SIGNAL ;
    SHAPE ABUTMENT ;
    PORT
      LAYER met2 ;
      RECT 398.290 0.000 398.430 0.420 ;
    END
  END rw0_rd_out[22]
  PIN rw0_rd_out[23]
    DIRECTION OUTPUT ;
    USE SIGNAL ;
    SHAPE ABUTMENT ;
    PORT
      LAYER met2 ;
      RECT 402.890 0.000 403.030 0.420 ;
    END
  END rw0_rd_out[23]
  PIN rw0_rd_out[24]
    DIRECTION OUTPUT ;
    USE SIGNAL ;
    SHAPE ABUTMENT ;
    PORT
      LAYER met2 ;
      RECT 407.490 0.000 407.630 0.420 ;
    END
  END rw0_rd_out[24]
  PIN rw0_rd_out[25]
    DIRECTION OUTPUT ;
    USE SIGNAL ;
    SHAPE ABUTMENT ;
    PORT
      LAYER met2 ;
      RECT 412.090 0.000 412.230 0.420 ;
    END
  END rw0_rd_out[25]
  PIN rw0_rd_out[26]
    DIRECTION OUTPUT ;
    USE SIGNAL ;
    SHAPE ABUTMENT ;
    PORT
      LAYER met2 ;
      RECT 416.690 0.000 416.830 0.420 ;
    END
  END rw0_rd_out[26]
  PIN rw0_rd_out[27]
    DIRECTION OUTPUT ;
    USE SIGNAL ;
    SHAPE ABUTMENT ;
    PORT
      LAYER met2 ;
      RECT 421.290 0.000 421.430 0.420 ;
    END
  END rw0_rd_out[27]
  PIN rw0_rd_out[28]
    DIRECTION OUTPUT ;
    USE SIGNAL ;
    SHAPE ABUTMENT ;
    PORT
      LAYER met2 ;
      RECT 425.890 0.000 426.030 0.420 ;
    END
  END rw0_rd_out[28]
  PIN rw0_rd_out[29]
    DIRECTION OUTPUT ;
    USE SIGNAL ;
    SHAPE ABUTMENT ;
    PORT
      LAYER met2 ;
      RECT 430.490 0.000 430.630 0.420 ;
    END
  END rw0_rd_out[29]
  PIN rw0_rd_out[30]
    DIRECTION OUTPUT ;
    USE SIGNAL ;
    SHAPE ABUTMENT ;
    PORT
      LAYER met2 ;
      RECT 435.090 0.000 435.230 0.420 ;
    END
  END rw0_rd_out[30]
  PIN rw0_rd_out[31]
    DIRECTION OUTPUT ;
    USE SIGNAL ;
    SHAPE ABUTMENT ;
    PORT
      LAYER met2 ;
      RECT 439.690 0.000 439.830 0.420 ;
    END
  END rw0_rd_out[31]
  PIN rw0_rd_out[32]
    DIRECTION OUTPUT ;
    USE SIGNAL ;
    SHAPE ABUTMENT ;
    PORT
      LAYER met2 ;
      RECT 2.690 1003.260 2.830 1003.680 ;
    END
  END rw0_rd_out[32]
  PIN rw0_rd_out[33]
    DIRECTION OUTPUT ;
    USE SIGNAL ;
    SHAPE ABUTMENT ;
    PORT
      LAYER met2 ;
      RECT 10.970 1003.260 11.110 1003.680 ;
    END
  END rw0_rd_out[33]
  PIN rw0_rd_out[34]
    DIRECTION OUTPUT ;
    USE SIGNAL ;
    SHAPE ABUTMENT ;
    PORT
      LAYER met2 ;
      RECT 19.250 1003.260 19.390 1003.680 ;
    END
  END rw0_rd_out[34]
  PIN rw0_rd_out[35]
    DIRECTION OUTPUT ;
    USE SIGNAL ;
    SHAPE ABUTMENT ;
    PORT
      LAYER met2 ;
      RECT 27.530 1003.260 27.670 1003.680 ;
    END
  END rw0_rd_out[35]
  PIN rw0_rd_out[36]
    DIRECTION OUTPUT ;
    USE SIGNAL ;
    SHAPE ABUTMENT ;
    PORT
      LAYER met2 ;
      RECT 35.810 1003.260 35.950 1003.680 ;
    END
  END rw0_rd_out[36]
  PIN rw0_rd_out[37]
    DIRECTION OUTPUT ;
    USE SIGNAL ;
    SHAPE ABUTMENT ;
    PORT
      LAYER met2 ;
      RECT 44.090 1003.260 44.230 1003.680 ;
    END
  END rw0_rd_out[37]
  PIN rw0_rd_out[38]
    DIRECTION OUTPUT ;
    USE SIGNAL ;
    SHAPE ABUTMENT ;
    PORT
      LAYER met2 ;
      RECT 52.370 1003.260 52.510 1003.680 ;
    END
  END rw0_rd_out[38]
  PIN rw0_rd_out[39]
    DIRECTION OUTPUT ;
    USE SIGNAL ;
    SHAPE ABUTMENT ;
    PORT
      LAYER met2 ;
      RECT 60.650 1003.260 60.790 1003.680 ;
    END
  END rw0_rd_out[39]
  PIN rw0_rd_out[40]
    DIRECTION OUTPUT ;
    USE SIGNAL ;
    SHAPE ABUTMENT ;
    PORT
      LAYER met2 ;
      RECT 68.930 1003.260 69.070 1003.680 ;
    END
  END rw0_rd_out[40]
  PIN rw0_rd_out[41]
    DIRECTION OUTPUT ;
    USE SIGNAL ;
    SHAPE ABUTMENT ;
    PORT
      LAYER met2 ;
      RECT 77.210 1003.260 77.350 1003.680 ;
    END
  END rw0_rd_out[41]
  PIN rw0_rd_out[42]
    DIRECTION OUTPUT ;
    USE SIGNAL ;
    SHAPE ABUTMENT ;
    PORT
      LAYER met2 ;
      RECT 85.490 1003.260 85.630 1003.680 ;
    END
  END rw0_rd_out[42]
  PIN rw0_rd_out[43]
    DIRECTION OUTPUT ;
    USE SIGNAL ;
    SHAPE ABUTMENT ;
    PORT
      LAYER met2 ;
      RECT 93.770 1003.260 93.910 1003.680 ;
    END
  END rw0_rd_out[43]
  PIN rw0_rd_out[44]
    DIRECTION OUTPUT ;
    USE SIGNAL ;
    SHAPE ABUTMENT ;
    PORT
      LAYER met2 ;
      RECT 102.050 1003.260 102.190 1003.680 ;
    END
  END rw0_rd_out[44]
  PIN rw0_rd_out[45]
    DIRECTION OUTPUT ;
    USE SIGNAL ;
    SHAPE ABUTMENT ;
    PORT
      LAYER met2 ;
      RECT 110.330 1003.260 110.470 1003.680 ;
    END
  END rw0_rd_out[45]
  PIN rw0_rd_out[46]
    DIRECTION OUTPUT ;
    USE SIGNAL ;
    SHAPE ABUTMENT ;
    PORT
      LAYER met2 ;
      RECT 118.610 1003.260 118.750 1003.680 ;
    END
  END rw0_rd_out[46]
  PIN rw0_rd_out[47]
    DIRECTION OUTPUT ;
    USE SIGNAL ;
    SHAPE ABUTMENT ;
    PORT
      LAYER met2 ;
      RECT 126.890 1003.260 127.030 1003.680 ;
    END
  END rw0_rd_out[47]
  PIN rw0_rd_out[48]
    DIRECTION OUTPUT ;
    USE SIGNAL ;
    SHAPE ABUTMENT ;
    PORT
      LAYER met2 ;
      RECT 135.170 1003.260 135.310 1003.680 ;
    END
  END rw0_rd_out[48]
  PIN rw0_rd_out[49]
    DIRECTION OUTPUT ;
    USE SIGNAL ;
    SHAPE ABUTMENT ;
    PORT
      LAYER met2 ;
      RECT 143.450 1003.260 143.590 1003.680 ;
    END
  END rw0_rd_out[49]
  PIN rw0_rd_out[50]
    DIRECTION OUTPUT ;
    USE SIGNAL ;
    SHAPE ABUTMENT ;
    PORT
      LAYER met2 ;
      RECT 151.730 1003.260 151.870 1003.680 ;
    END
  END rw0_rd_out[50]
  PIN rw0_rd_out[51]
    DIRECTION OUTPUT ;
    USE SIGNAL ;
    SHAPE ABUTMENT ;
    PORT
      LAYER met2 ;
      RECT 160.010 1003.260 160.150 1003.680 ;
    END
  END rw0_rd_out[51]
  PIN rw0_rd_out[52]
    DIRECTION OUTPUT ;
    USE SIGNAL ;
    SHAPE ABUTMENT ;
    PORT
      LAYER met2 ;
      RECT 168.290 1003.260 168.430 1003.680 ;
    END
  END rw0_rd_out[52]
  PIN rw0_rd_out[53]
    DIRECTION OUTPUT ;
    USE SIGNAL ;
    SHAPE ABUTMENT ;
    PORT
      LAYER met2 ;
      RECT 176.570 1003.260 176.710 1003.680 ;
    END
  END rw0_rd_out[53]
  PIN rw0_rd_out[54]
    DIRECTION OUTPUT ;
    USE SIGNAL ;
    SHAPE ABUTMENT ;
    PORT
      LAYER met2 ;
      RECT 184.850 1003.260 184.990 1003.680 ;
    END
  END rw0_rd_out[54]
  PIN rw0_rd_out[55]
    DIRECTION OUTPUT ;
    USE SIGNAL ;
    SHAPE ABUTMENT ;
    PORT
      LAYER met2 ;
      RECT 193.130 1003.260 193.270 1003.680 ;
    END
  END rw0_rd_out[55]
  PIN rw0_rd_out[56]
    DIRECTION OUTPUT ;
    USE SIGNAL ;
    SHAPE ABUTMENT ;
    PORT
      LAYER met2 ;
      RECT 201.410 1003.260 201.550 1003.680 ;
    END
  END rw0_rd_out[56]
  PIN rw0_rd_out[57]
    DIRECTION OUTPUT ;
    USE SIGNAL ;
    SHAPE ABUTMENT ;
    PORT
      LAYER met2 ;
      RECT 209.690 1003.260 209.830 1003.680 ;
    END
  END rw0_rd_out[57]
  PIN rw0_rd_out[58]
    DIRECTION OUTPUT ;
    USE SIGNAL ;
    SHAPE ABUTMENT ;
    PORT
      LAYER met2 ;
      RECT 217.970 1003.260 218.110 1003.680 ;
    END
  END rw0_rd_out[58]
  PIN rw0_rd_out[59]
    DIRECTION OUTPUT ;
    USE SIGNAL ;
    SHAPE ABUTMENT ;
    PORT
      LAYER met2 ;
      RECT 226.250 1003.260 226.390 1003.680 ;
    END
  END rw0_rd_out[59]
  PIN rw0_rd_out[60]
    DIRECTION OUTPUT ;
    USE SIGNAL ;
    SHAPE ABUTMENT ;
    PORT
      LAYER met2 ;
      RECT 234.530 1003.260 234.670 1003.680 ;
    END
  END rw0_rd_out[60]
  PIN rw0_rd_out[61]
    DIRECTION OUTPUT ;
    USE SIGNAL ;
    SHAPE ABUTMENT ;
    PORT
      LAYER met2 ;
      RECT 242.810 1003.260 242.950 1003.680 ;
    END
  END rw0_rd_out[61]
  PIN rw0_rd_out[62]
    DIRECTION OUTPUT ;
    USE SIGNAL ;
    SHAPE ABUTMENT ;
    PORT
      LAYER met2 ;
      RECT 251.090 1003.260 251.230 1003.680 ;
    END
  END rw0_rd_out[62]
  PIN rw0_rd_out[63]
    DIRECTION OUTPUT ;
    USE SIGNAL ;
    SHAPE ABUTMENT ;
    PORT
      LAYER met2 ;
      RECT 259.370 1003.260 259.510 1003.680 ;
    END
  END rw0_rd_out[63]
  PIN rw1_rd_out[0]
    DIRECTION OUTPUT ;
    USE SIGNAL ;
    SHAPE ABUTMENT ;
    PORT
      LAYER met2 ;
      RECT 444.290 0.000 444.430 0.420 ;
    END
  END rw1_rd_out[0]
  PIN rw1_rd_out[1]
    DIRECTION OUTPUT ;
    USE SIGNAL ;
    SHAPE ABUTMENT ;
    PORT
      LAYER met2 ;
      RECT 448.890 0.000 449.030 0.420 ;
    END
  END rw1_rd_out[1]
  PIN rw1_rd_out[2]
    DIRECTION OUTPUT ;
    USE SIGNAL ;
    SHAPE ABUTMENT ;
    PORT
      LAYER met2 ;
      RECT 453.490 0.000 453.630 0.420 ;
    END
  END rw1_rd_out[2]
  PIN rw1_rd_out[3]
    DIRECTION OUTPUT ;
    USE SIGNAL ;
    SHAPE ABUTMENT ;
    PORT
      LAYER met2 ;
      RECT 458.090 0.000 458.230 0.420 ;
    END
  END rw1_rd_out[3]
  PIN rw1_rd_out[4]
    DIRECTION OUTPUT ;
    USE SIGNAL ;
    SHAPE ABUTMENT ;
    PORT
      LAYER met2 ;
      RECT 462.690 0.000 462.830 0.420 ;
    END
  END rw1_rd_out[4]
  PIN rw1_rd_out[5]
    DIRECTION OUTPUT ;
    USE SIGNAL ;
    SHAPE ABUTMENT ;
    PORT
      LAYER met2 ;
      RECT 467.290 0.000 467.430 0.420 ;
    END
  END rw1_rd_out[5]
  PIN rw1_rd_out[6]
    DIRECTION OUTPUT ;
    USE SIGNAL ;
    SHAPE ABUTMENT ;
    PORT
      LAYER met2 ;
      RECT 471.890 0.000 472.030 0.420 ;
    END
  END rw1_rd_out[6]
  PIN rw1_rd_out[7]
    DIRECTION OUTPUT ;
    USE SIGNAL ;
    SHAPE ABUTMENT ;
    PORT
      LAYER met2 ;
      RECT 476.490 0.000 476.630 0.420 ;
    END
  END rw1_rd_out[7]
  PIN rw1_rd_out[8]
    DIRECTION OUTPUT ;
    USE SIGNAL ;
    SHAPE ABUTMENT ;
    PORT
      LAYER met2 ;
      RECT 481.090 0.000 481.230 0.420 ;
    END
  END rw1_rd_out[8]
  PIN rw1_rd_out[9]
    DIRECTION OUTPUT ;
    USE SIGNAL ;
    SHAPE ABUTMENT ;
    PORT
      LAYER met2 ;
      RECT 485.690 0.000 485.830 0.420 ;
    END
  END rw1_rd_out[9]
  PIN rw1_rd_out[10]
    DIRECTION OUTPUT ;
    USE SIGNAL ;
    SHAPE ABUTMENT ;
    PORT
      LAYER met2 ;
      RECT 490.290 0.000 490.430 0.420 ;
    END
  END rw1_rd_out[10]
  PIN rw1_rd_out[11]
    DIRECTION OUTPUT ;
    USE SIGNAL ;
    SHAPE ABUTMENT ;
    PORT
      LAYER met2 ;
      RECT 494.890 0.000 495.030 0.420 ;
    END
  END rw1_rd_out[11]
  PIN rw1_rd_out[12]
    DIRECTION OUTPUT ;
    USE SIGNAL ;
    SHAPE ABUTMENT ;
    PORT
      LAYER met2 ;
      RECT 499.490 0.000 499.630 0.420 ;
    END
  END rw1_rd_out[12]
  PIN rw1_rd_out[13]
    DIRECTION OUTPUT ;
    USE SIGNAL ;
    SHAPE ABUTMENT ;
    PORT
      LAYER met2 ;
      RECT 504.090 0.000 504.230 0.420 ;
    END
  END rw1_rd_out[13]
  PIN rw1_rd_out[14]
    DIRECTION OUTPUT ;
    USE SIGNAL ;
    SHAPE ABUTMENT ;
    PORT
      LAYER met2 ;
      RECT 508.690 0.000 508.830 0.420 ;
    END
  END rw1_rd_out[14]
  PIN rw1_rd_out[15]
    DIRECTION OUTPUT ;
    USE SIGNAL ;
    SHAPE ABUTMENT ;
    PORT
      LAYER met2 ;
      RECT 513.290 0.000 513.430 0.420 ;
    END
  END rw1_rd_out[15]
  PIN rw1_rd_out[16]
    DIRECTION OUTPUT ;
    USE SIGNAL ;
    SHAPE ABUTMENT ;
    PORT
      LAYER met2 ;
      RECT 517.890 0.000 518.030 0.420 ;
    END
  END rw1_rd_out[16]
  PIN rw1_rd_out[17]
    DIRECTION OUTPUT ;
    USE SIGNAL ;
    SHAPE ABUTMENT ;
    PORT
      LAYER met2 ;
      RECT 522.490 0.000 522.630 0.420 ;
    END
  END rw1_rd_out[17]
  PIN rw1_rd_out[18]
    DIRECTION OUTPUT ;
    USE SIGNAL ;
    SHAPE ABUTMENT ;
    PORT
      LAYER met2 ;
      RECT 527.090 0.000 527.230 0.420 ;
    END
  END rw1_rd_out[18]
  PIN rw1_rd_out[19]
    DIRECTION OUTPUT ;
    USE SIGNAL ;
    SHAPE ABUTMENT ;
    PORT
      LAYER met2 ;
      RECT 531.690 0.000 531.830 0.420 ;
    END
  END rw1_rd_out[19]
  PIN rw1_rd_out[20]
    DIRECTION OUTPUT ;
    USE SIGNAL ;
    SHAPE ABUTMENT ;
    PORT
      LAYER met2 ;
      RECT 536.290 0.000 536.430 0.420 ;
    END
  END rw1_rd_out[20]
  PIN rw1_rd_out[21]
    DIRECTION OUTPUT ;
    USE SIGNAL ;
    SHAPE ABUTMENT ;
    PORT
      LAYER met2 ;
      RECT 540.890 0.000 541.030 0.420 ;
    END
  END rw1_rd_out[21]
  PIN rw1_rd_out[22]
    DIRECTION OUTPUT ;
    USE SIGNAL ;
    SHAPE ABUTMENT ;
    PORT
      LAYER met2 ;
      RECT 545.490 0.000 545.630 0.420 ;
    END
  END rw1_rd_out[22]
  PIN rw1_rd_out[23]
    DIRECTION OUTPUT ;
    USE SIGNAL ;
    SHAPE ABUTMENT ;
    PORT
      LAYER met2 ;
      RECT 550.090 0.000 550.230 0.420 ;
    END
  END rw1_rd_out[23]
  PIN rw1_rd_out[24]
    DIRECTION OUTPUT ;
    USE SIGNAL ;
    SHAPE ABUTMENT ;
    PORT
      LAYER met2 ;
      RECT 554.690 0.000 554.830 0.420 ;
    END
  END rw1_rd_out[24]
  PIN rw1_rd_out[25]
    DIRECTION OUTPUT ;
    USE SIGNAL ;
    SHAPE ABUTMENT ;
    PORT
      LAYER met2 ;
      RECT 559.290 0.000 559.430 0.420 ;
    END
  END rw1_rd_out[25]
  PIN rw1_rd_out[26]
    DIRECTION OUTPUT ;
    USE SIGNAL ;
    SHAPE ABUTMENT ;
    PORT
      LAYER met2 ;
      RECT 563.890 0.000 564.030 0.420 ;
    END
  END rw1_rd_out[26]
  PIN rw1_rd_out[27]
    DIRECTION OUTPUT ;
    USE SIGNAL ;
    SHAPE ABUTMENT ;
    PORT
      LAYER met2 ;
      RECT 568.490 0.000 568.630 0.420 ;
    END
  END rw1_rd_out[27]
  PIN rw1_rd_out[28]
    DIRECTION OUTPUT ;
    USE SIGNAL ;
    SHAPE ABUTMENT ;
    PORT
      LAYER met2 ;
      RECT 573.090 0.000 573.230 0.420 ;
    END
  END rw1_rd_out[28]
  PIN rw1_rd_out[29]
    DIRECTION OUTPUT ;
    USE SIGNAL ;
    SHAPE ABUTMENT ;
    PORT
      LAYER met2 ;
      RECT 577.690 0.000 577.830 0.420 ;
    END
  END rw1_rd_out[29]
  PIN rw1_rd_out[30]
    DIRECTION OUTPUT ;
    USE SIGNAL ;
    SHAPE ABUTMENT ;
    PORT
      LAYER met2 ;
      RECT 582.290 0.000 582.430 0.420 ;
    END
  END rw1_rd_out[30]
  PIN rw1_rd_out[31]
    DIRECTION OUTPUT ;
    USE SIGNAL ;
    SHAPE ABUTMENT ;
    PORT
      LAYER met2 ;
      RECT 586.890 0.000 587.030 0.420 ;
    END
  END rw1_rd_out[31]
  PIN rw1_rd_out[32]
    DIRECTION OUTPUT ;
    USE SIGNAL ;
    SHAPE ABUTMENT ;
    PORT
      LAYER met2 ;
      RECT 267.650 1003.260 267.790 1003.680 ;
    END
  END rw1_rd_out[32]
  PIN rw1_rd_out[33]
    DIRECTION OUTPUT ;
    USE SIGNAL ;
    SHAPE ABUTMENT ;
    PORT
      LAYER met2 ;
      RECT 275.930 1003.260 276.070 1003.680 ;
    END
  END rw1_rd_out[33]
  PIN rw1_rd_out[34]
    DIRECTION OUTPUT ;
    USE SIGNAL ;
    SHAPE ABUTMENT ;
    PORT
      LAYER met2 ;
      RECT 284.210 1003.260 284.350 1003.680 ;
    END
  END rw1_rd_out[34]
  PIN rw1_rd_out[35]
    DIRECTION OUTPUT ;
    USE SIGNAL ;
    SHAPE ABUTMENT ;
    PORT
      LAYER met2 ;
      RECT 292.490 1003.260 292.630 1003.680 ;
    END
  END rw1_rd_out[35]
  PIN rw1_rd_out[36]
    DIRECTION OUTPUT ;
    USE SIGNAL ;
    SHAPE ABUTMENT ;
    PORT
      LAYER met2 ;
      RECT 300.770 1003.260 300.910 1003.680 ;
    END
  END rw1_rd_out[36]
  PIN rw1_rd_out[37]
    DIRECTION OUTPUT ;
    USE SIGNAL ;
    SHAPE ABUTMENT ;
    PORT
      LAYER met2 ;
      RECT 309.050 1003.260 309.190 1003.680 ;
    END
  END rw1_rd_out[37]
  PIN rw1_rd_out[38]
    DIRECTION OUTPUT ;
    USE SIGNAL ;
    SHAPE ABUTMENT ;
    PORT
      LAYER met2 ;
      RECT 317.330 1003.260 317.470 1003.680 ;
    END
  END rw1_rd_out[38]
  PIN rw1_rd_out[39]
    DIRECTION OUTPUT ;
    USE SIGNAL ;
    SHAPE ABUTMENT ;
    PORT
      LAYER met2 ;
      RECT 325.610 1003.260 325.750 1003.680 ;
    END
  END rw1_rd_out[39]
  PIN rw1_rd_out[40]
    DIRECTION OUTPUT ;
    USE SIGNAL ;
    SHAPE ABUTMENT ;
    PORT
      LAYER met2 ;
      RECT 333.890 1003.260 334.030 1003.680 ;
    END
  END rw1_rd_out[40]
  PIN rw1_rd_out[41]
    DIRECTION OUTPUT ;
    USE SIGNAL ;
    SHAPE ABUTMENT ;
    PORT
      LAYER met2 ;
      RECT 342.170 1003.260 342.310 1003.680 ;
    END
  END rw1_rd_out[41]
  PIN rw1_rd_out[42]
    DIRECTION OUTPUT ;
    USE SIGNAL ;
    SHAPE ABUTMENT ;
    PORT
      LAYER met2 ;
      RECT 350.450 1003.260 350.590 1003.680 ;
    END
  END rw1_rd_out[42]
  PIN rw1_rd_out[43]
    DIRECTION OUTPUT ;
    USE SIGNAL ;
    SHAPE ABUTMENT ;
    PORT
      LAYER met2 ;
      RECT 358.730 1003.260 358.870 1003.680 ;
    END
  END rw1_rd_out[43]
  PIN rw1_rd_out[44]
    DIRECTION OUTPUT ;
    USE SIGNAL ;
    SHAPE ABUTMENT ;
    PORT
      LAYER met2 ;
      RECT 367.010 1003.260 367.150 1003.680 ;
    END
  END rw1_rd_out[44]
  PIN rw1_rd_out[45]
    DIRECTION OUTPUT ;
    USE SIGNAL ;
    SHAPE ABUTMENT ;
    PORT
      LAYER met2 ;
      RECT 375.290 1003.260 375.430 1003.680 ;
    END
  END rw1_rd_out[45]
  PIN rw1_rd_out[46]
    DIRECTION OUTPUT ;
    USE SIGNAL ;
    SHAPE ABUTMENT ;
    PORT
      LAYER met2 ;
      RECT 383.570 1003.260 383.710 1003.680 ;
    END
  END rw1_rd_out[46]
  PIN rw1_rd_out[47]
    DIRECTION OUTPUT ;
    USE SIGNAL ;
    SHAPE ABUTMENT ;
    PORT
      LAYER met2 ;
      RECT 391.850 1003.260 391.990 1003.680 ;
    END
  END rw1_rd_out[47]
  PIN rw1_rd_out[48]
    DIRECTION OUTPUT ;
    USE SIGNAL ;
    SHAPE ABUTMENT ;
    PORT
      LAYER met2 ;
      RECT 400.130 1003.260 400.270 1003.680 ;
    END
  END rw1_rd_out[48]
  PIN rw1_rd_out[49]
    DIRECTION OUTPUT ;
    USE SIGNAL ;
    SHAPE ABUTMENT ;
    PORT
      LAYER met2 ;
      RECT 408.410 1003.260 408.550 1003.680 ;
    END
  END rw1_rd_out[49]
  PIN rw1_rd_out[50]
    DIRECTION OUTPUT ;
    USE SIGNAL ;
    SHAPE ABUTMENT ;
    PORT
      LAYER met2 ;
      RECT 416.690 1003.260 416.830 1003.680 ;
    END
  END rw1_rd_out[50]
  PIN rw1_rd_out[51]
    DIRECTION OUTPUT ;
    USE SIGNAL ;
    SHAPE ABUTMENT ;
    PORT
      LAYER met2 ;
      RECT 424.970 1003.260 425.110 1003.680 ;
    END
  END rw1_rd_out[51]
  PIN rw1_rd_out[52]
    DIRECTION OUTPUT ;
    USE SIGNAL ;
    SHAPE ABUTMENT ;
    PORT
      LAYER met2 ;
      RECT 433.250 1003.260 433.390 1003.680 ;
    END
  END rw1_rd_out[52]
  PIN rw1_rd_out[53]
    DIRECTION OUTPUT ;
    USE SIGNAL ;
    SHAPE ABUTMENT ;
    PORT
      LAYER met2 ;
      RECT 441.530 1003.260 441.670 1003.680 ;
    END
  END rw1_rd_out[53]
  PIN rw1_rd_out[54]
    DIRECTION OUTPUT ;
    USE SIGNAL ;
    SHAPE ABUTMENT ;
    PORT
      LAYER met2 ;
      RECT 449.810 1003.260 449.950 1003.680 ;
    END
  END rw1_rd_out[54]
  PIN rw1_rd_out[55]
    DIRECTION OUTPUT ;
    USE SIGNAL ;
    SHAPE ABUTMENT ;
    PORT
      LAYER met2 ;
      RECT 458.090 1003.260 458.230 1003.680 ;
    END
  END rw1_rd_out[55]
  PIN rw1_rd_out[56]
    DIRECTION OUTPUT ;
    USE SIGNAL ;
    SHAPE ABUTMENT ;
    PORT
      LAYER met2 ;
      RECT 466.370 1003.260 466.510 1003.680 ;
    END
  END rw1_rd_out[56]
  PIN rw1_rd_out[57]
    DIRECTION OUTPUT ;
    USE SIGNAL ;
    SHAPE ABUTMENT ;
    PORT
      LAYER met2 ;
      RECT 474.650 1003.260 474.790 1003.680 ;
    END
  END rw1_rd_out[57]
  PIN rw1_rd_out[58]
    DIRECTION OUTPUT ;
    USE SIGNAL ;
    SHAPE ABUTMENT ;
    PORT
      LAYER met2 ;
      RECT 482.930 1003.260 483.070 1003.680 ;
    END
  END rw1_rd_out[58]
  PIN rw1_rd_out[59]
    DIRECTION OUTPUT ;
    USE SIGNAL ;
    SHAPE ABUTMENT ;
    PORT
      LAYER met2 ;
      RECT 491.210 1003.260 491.350 1003.680 ;
    END
  END rw1_rd_out[59]
  PIN rw1_rd_out[60]
    DIRECTION OUTPUT ;
    USE SIGNAL ;
    SHAPE ABUTMENT ;
    PORT
      LAYER met2 ;
      RECT 499.490 1003.260 499.630 1003.680 ;
    END
  END rw1_rd_out[60]
  PIN rw1_rd_out[61]
    DIRECTION OUTPUT ;
    USE SIGNAL ;
    SHAPE ABUTMENT ;
    PORT
      LAYER met2 ;
      RECT 507.770 1003.260 507.910 1003.680 ;
    END
  END rw1_rd_out[61]
  PIN rw1_rd_out[62]
    DIRECTION OUTPUT ;
    USE SIGNAL ;
    SHAPE ABUTMENT ;
    PORT
      LAYER met2 ;
      RECT 516.050 1003.260 516.190 1003.680 ;
    END
  END rw1_rd_out[62]
  PIN rw1_rd_out[63]
    DIRECTION OUTPUT ;
    USE SIGNAL ;
    SHAPE ABUTMENT ;
    PORT
      LAYER met2 ;
      RECT 524.330 1003.260 524.470 1003.680 ;
    END
  END rw1_rd_out[63]
  PIN rw0_addr_in[0]
    DIRECTION INPUT ;
    USE SIGNAL ;
    SHAPE ABUTMENT ;
    PORT
      LAYER met3 ;
      RECT 0.000 787.290 0.900 787.590 ;
    END
  END rw0_addr_in[0]
  PIN rw0_addr_in[1]
    DIRECTION INPUT ;
    USE SIGNAL ;
    SHAPE ABUTMENT ;
    PORT
      LAYER met3 ;
      RECT 0.000 811.770 0.900 812.070 ;
    END
  END rw0_addr_in[1]
  PIN rw0_addr_in[2]
    DIRECTION INPUT ;
    USE SIGNAL ;
    SHAPE ABUTMENT ;
    PORT
      LAYER met3 ;
      RECT 0.000 836.250 0.900 836.550 ;
    END
  END rw0_addr_in[2]
  PIN rw0_addr_in[3]
    DIRECTION INPUT ;
    USE SIGNAL ;
    SHAPE ABUTMENT ;
    PORT
      LAYER met3 ;
      RECT 0.000 860.730 0.900 861.030 ;
    END
  END rw0_addr_in[3]
  PIN rw0_addr_in[4]
    DIRECTION INPUT ;
    USE SIGNAL ;
    SHAPE ABUTMENT ;
    PORT
      LAYER met3 ;
      RECT 615.500 787.290 616.400 787.590 ;
    END
  END rw0_addr_in[4]
  PIN rw0_addr_in[5]
    DIRECTION INPUT ;
    USE SIGNAL ;
    SHAPE ABUTMENT ;
    PORT
      LAYER met3 ;
      RECT 615.500 811.770 616.400 812.070 ;
    END
  END rw0_addr_in[5]
  PIN rw0_addr_in[6]
    DIRECTION INPUT ;
    USE SIGNAL ;
    SHAPE ABUTMENT ;
    PORT
      LAYER met3 ;
      RECT 615.500 836.250 616.400 836.550 ;
    END
  END rw0_addr_in[6]
  PIN rw0_addr_in[7]
    DIRECTION INPUT ;
    USE SIGNAL ;
    SHAPE ABUTMENT ;
    PORT
      LAYER met3 ;
      RECT 615.500 860.730 616.400 861.030 ;
    END
  END rw0_addr_in[7]
  PIN rw1_addr_in[0]
    DIRECTION INPUT ;
    USE SIGNAL ;
    SHAPE ABUTMENT ;
    PORT
      LAYER met3 ;
      RECT 0.000 885.210 0.900 885.510 ;
    END
  END rw1_addr_in[0]
  PIN rw1_addr_in[1]
    DIRECTION INPUT ;
    USE SIGNAL ;
    SHAPE ABUTMENT ;
    PORT
      LAYER met3 ;
      RECT 0.000 909.690 0.900 909.990 ;
    END
  END rw1_addr_in[1]
  PIN rw1_addr_in[2]
    DIRECTION INPUT ;
    USE SIGNAL ;
    SHAPE ABUTMENT ;
    PORT
      LAYER met3 ;
      RECT 0.000 934.170 0.900 934.470 ;
    END
  END rw1_addr_in[2]
  PIN rw1_addr_in[3]
    DIRECTION INPUT ;
    USE SIGNAL ;
    SHAPE ABUTMENT ;
    PORT
      LAYER met3 ;
      RECT 0.000 958.650 0.900 958.950 ;
    END
  END rw1_addr_in[3]
  PIN rw1_addr_in[4]
    DIRECTION INPUT ;
    USE SIGNAL ;
    SHAPE ABUTMENT ;
    PORT
      LAYER met3 ;
      RECT 615.500 885.210 616.400 885.510 ;
    END
  END rw1_addr_in[4]
  PIN rw1_addr_in[5]
    DIRECTION INPUT ;
    USE SIGNAL ;
    SHAPE ABUTMENT ;
    PORT
      LAYER met3 ;
      RECT 615.500 909.690 616.400 909.990 ;
    END
  END rw1_addr_in[5]
  PIN rw1_addr_in[6]
    DIRECTION INPUT ;
    USE SIGNAL ;
    SHAPE ABUTMENT ;
    PORT
      LAYER met3 ;
      RECT 615.500 934.170 616.400 934.470 ;
    END
  END rw1_addr_in[6]
  PIN rw1_addr_in[7]
    DIRECTION INPUT ;
    USE SIGNAL ;
    SHAPE ABUTMENT ;
    PORT
      LAYER met3 ;
      RECT 615.500 958.650 616.400 958.950 ;
    END
  END rw1_addr_in[7]
  PIN rw0_we_in
    DIRECTION INPUT ;
    USE SIGNAL ;
    SHAPE ABUTMENT ;
    PORT
      LAYER met2 ;
      RECT 532.610 1003.260 532.750 1003.680 ;
    END
  END rw0_we_in
  PIN rw0_ce_in
    DIRECTION INPUT ;
    USE SIGNAL ;
    SHAPE ABUTMENT ;
    PORT
      LAYER met2 ;
      RECT 540.890 1003.260 541.030 1003.680 ;
    END
  END rw0_ce_in
  PIN rw0_clk
    DIRECTION INPUT ;
    USE SIGNAL ;
    SHAPE ABUTMENT ;
    PORT
      LAYER met2 ;
      RECT 549.170 1003.260 549.310 1003.680 ;
    END
  END rw0_clk
  PIN rw1_we_in
    DIRECTION INPUT ;
    USE SIGNAL ;
    SHAPE ABUTMENT ;
    PORT
      LAYER met2 ;
      RECT 557.450 1003.260 557.590 1003.680 ;
    END
  END rw1_we_in
  PIN rw1_ce_in
    DIRECTION INPUT ;
    USE SIGNAL ;
    SHAPE ABUTMENT ;
    PORT
      LAYER met2 ;
      RECT 565.730 1003.260 565.870 1003.680 ;
    END
  END rw1_ce_in
  PIN rw1_clk
    DIRECTION INPUT ;
    USE SIGNAL ;
    SHAPE ABUTMENT ;
    PORT
      LAYER met2 ;
      RECT 574.010 1003.260 574.150 1003.680 ;
    END
  END rw1_clk
  PIN VSS
    DIRECTION INOUT ;
    USE GROUND ;
    PORT
      LAYER met4 ;
      RECT 2.160 4.080 3.360 999.600 ;
      RECT 13.040 4.080 14.240 999.600 ;
      RECT 23.920 4.080 25.120 999.600 ;
      RECT 34.800 4.080 36.000 999.600 ;
      RECT 45.680 4.080 46.880 999.600 ;
      RECT 56.560 4.080 57.760 999.600 ;
      RECT 67.440 4.080 68.640 999.600 ;
      RECT 78.320 4.080 79.520 999.600 ;
      RECT 89.200 4.080 90.400 999.600 ;
      RECT 100.080 4.080 101.280 999.600 ;
      RECT 110.960 4.080 112.160 999.600 ;
      RECT 121.840 4.080 123.040 999.600 ;
      RECT 132.720 4.080 133.920 999.600 ;
      RECT 143.600 4.080 144.800 999.600 ;
      RECT 154.480 4.080 155.680 999.600 ;
      RECT 165.360 4.080 166.560 999.600 ;
      RECT 176.240 4.080 177.440 999.600 ;
      RECT 187.120 4.080 188.320 999.600 ;
      RECT 198.000 4.080 199.200 999.600 ;
      RECT 208.880 4.080 210.080 999.600 ;
      RECT 219.760 4.080 220.960 999.600 ;
      RECT 230.640 4.080 231.840 999.600 ;
      RECT 241.520 4.080 242.720 999.600 ;
      RECT 252.400 4.080 253.600 999.600 ;
      RECT 263.280 4.080 264.480 999.600 ;
      RECT 274.160 4.080 275.360 999.600 ;
      RECT 285.040 4.080 286.240 999.600 ;
      RECT 295.920 4.080 297.120 999.600 ;
      RECT 306.800 4.080 308.000 999.600 ;
      RECT 317.680 4.080 318.880 999.600 ;
      RECT 328.560 4.080 329.760 999.600 ;
      RECT 339.440 4.080 340.640 999.600 ;
      RECT 350.320 4.080 351.520 999.600 ;
      RECT 361.200 4.080 362.400 999.600 ;
      RECT 372.080 4.080 373.280 999.600 ;
      RECT 382.960 4.080 384.160 999.600 ;
      RECT 393.840 4.080 395.040 999.600 ;
      RECT 404.720 4.080 405.920 999.600 ;
      RECT 415.600 4.080 416.800 999.600 ;
      RECT 426.480 4.080 427.680 999.600 ;
      RECT 437.360 4.080 438.560 999.600 ;
      RECT 448.240 4.080 449.440 999.600 ;
      RECT 459.120 4.080 460.320 999.600 ;
      RECT 470.000 4.080 471.200 999.600 ;
      RECT 480.880 4.080 482.080 999.600 ;
      RECT 491.760 4.080 492.960 999.600 ;
      RECT 502.640 4.080 503.840 999.600 ;
      RECT 513.520 4.080 514.720 999.600 ;
      RECT 524.400 4.080 525.600 999.600 ;
      RECT 535.280 4.080 536.480 999.600 ;
      RECT 546.160 4.080 547.360 999.600 ;
      RECT 557.040 4.080 558.240 999.600 ;
      RECT 567.920 4.080 569.120 999.600 ;
      RECT 578.800 4.080 580.000 999.600 ;
      RECT 589.680 4.080 590.880 999.600 ;
      RECT 600.560 4.080 601.760 999.600 ;
      RECT 611.440 4.080 612.640 999.600 ;
    END
  END VSS
  PIN VDD
    DIRECTION INOUT ;
    USE POWER ;
    PORT
      LAYER met4 ;
      RECT 7.600 4.080 8.800 999.600 ;
      RECT 18.480 4.080 19.680 999.600 ;
      RECT 29.360 4.080 30.560 999.600 ;
      RECT 40.240 4.080 41.440 999.600 ;
      RECT 51.120 4.080 52.320 999.600 ;
      RECT 62.000 4.080 63.200 999.600 ;
      RECT 72.880 4.080 74.080 999.600 ;
      RECT 83.760 4.080 84.960 999.600 ;
      RECT 94.640 4.080 95.840 999.600 ;
      RECT 105.520 4.080 106.720 999.600 ;
      RECT 116.400 4.080 117.600 999.600 ;
      RECT 127.280 4.080 128.480 999.600 ;
      RECT 138.160 4.080 139.360 999.600 ;
      RECT 149.040 4.080 150.240 999.600 ;
      RECT 159.920 4.080 161.120 999.600 ;
      RECT 170.800 4.080 172.000 999.600 ;
      RECT 181.680 4.080 182.880 999.600 ;
      RECT 192.560 4.080 193.760 999.600 ;
      RECT 203.440 4.080 204.640 999.600 ;
      RECT 214.320 4.080 215.520 999.600 ;
      RECT 225.200 4.080 226.400 999.600 ;
      RECT 236.080 4.080 237.280 999.600 ;
      RECT 246.960 4.080 248.160 999.600 ;
      RECT 257.840 4.080 259.040 999.600 ;
      RECT 268.720 4.080 269.920 999.600 ;
      RECT 279.600 4.080 280.800 999.600 ;
      RECT 290.480 4.080 291.680 999.600 ;
      RECT 301.360 4.080 302.560 999.600 ;
      RECT 312.240 4.080 313.440 999.600 ;
      RECT 323.120 4.080 324.320 999.600 ;
      RECT 334.000 4.080 335.200 999.600 ;
      RECT 344.880 4.080 346.080 999.600 ;
      RECT 355.760 4.080 356.960 999.600 ;
      RECT 366.640 4.080 367.840 999.600 ;
      RECT 377.520 4.080 378.720 999.600 ;
      RECT 388.400 4.080 389.600 999.600 ;
      RECT 399.280 4.080 400.480 999.600 ;
      RECT 410.160 4.080 411.360 999.600 ;
      RECT 421.040 4.080 422.240 999.600 ;
      RECT 431.920 4.080 433.120 999.600 ;
      RECT 442.800 4.080 444.000 999.600 ;
      RECT 453.680 4.080 454.880 999.600 ;
      RECT 464.560 4.080 465.760 999.600 ;
      RECT 475.440 4.080 476.640 999.600 ;
      RECT 486.320 4.080 487.520 999.600 ;
      RECT 497.200 4.080 498.400 999.600 ;
      RECT 508.080 4.080 509.280 999.600 ;
      RECT 518.960 4.080 520.160 999.600 ;
      RECT 529.840 4.080 531.040 999.600 ;
      RECT 540.720 4.080 541.920 999.600 ;
      RECT 551.600 4.080 552.800 999.600 ;
      RECT 562.480 4.080 563.680 999.600 ;
      RECT 573.360 4.080 574.560 999.600 ;
      RECT 584.240 4.080 585.440 999.600 ;
      RECT 595.120 4.080 596.320 999.600 ;
      RECT 606.000 4.080 607.200 999.600 ;
    END
  END VDD
  OBS
    LAYER met1 ;
    RECT 0 0 616.400 1003.680 ;
    LAYER met2 ;
    RECT 0 0 616.400 1003.680 ;
    LAYER met3 ;
    RECT 0 0 616.400 1003.680 ;
    LAYER met4 ;
    RECT 0 0 616.400 1003.680 ;
  END
END fakeram_w64_l256

END LIBRARY
